VERSION 5.7 ;
  NOWIREEXTENSIONATPIN ON ;
  DIVIDERCHAR "/" ;
  BUSBITCHARS "[]" ;
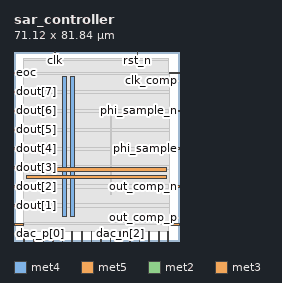
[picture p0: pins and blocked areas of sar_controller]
MACRO sar_controller
  CLASS BLOCK ;
  FOREIGN sar_controller ;
  ORIGIN 0.000 0.000 ;
  SIZE 71.120 BY 81.840 ;
  PIN VGND
    DIRECTION INOUT ;
    USE GROUND ;
    PORT
      LAYER met4 ;
        RECT 24.340 10.640 25.940 70.960 ;
    END
    PORT
      LAYER met5 ;
        RECT 5.280 30.030 65.560 31.630 ;
    END
  END VGND
  PIN VPWR
    DIRECTION INOUT ;
    USE POWER ;
    PORT
      LAYER met4 ;
        RECT 21.040 10.640 22.640 70.960 ;
    END
    PORT
      LAYER met5 ;
        RECT 5.280 26.730 65.560 28.330 ;
    END
  END VPWR
  PIN clk
    DIRECTION INPUT ;
    USE SIGNAL ;
    ANTENNAGATEAREA 1.704000 ;
    PORT
      LAYER met2 ;
        RECT 17.570 77.840 17.850 81.840 ;
    END
  END clk
  PIN clk_comp
    DIRECTION OUTPUT ;
    USE SIGNAL ;
    ANTENNADIFFAREA 0.340600 ;
    PORT
      LAYER met3 ;
        RECT 67.120 72.120 71.120 72.720 ;
    END
  END clk_comp
  PIN dac_n[0]
    DIRECTION OUTPUT ;
    USE SIGNAL ;
    ANTENNADIFFAREA 0.340600 ;
    PORT
      LAYER met2 ;
        RECT 37.350 0.000 37.630 4.000 ;
    END
  END dac_n[0]
  PIN dac_n[1]
    DIRECTION OUTPUT ;
    USE SIGNAL ;
    ANTENNADIFFAREA 0.340600 ;
    PORT
      LAYER met2 ;
        RECT 41.490 0.000 41.770 4.000 ;
    END
  END dac_n[1]
  PIN dac_n[2]
    DIRECTION OUTPUT ;
    USE SIGNAL ;
    ANTENNADIFFAREA 0.340600 ;
    PORT
      LAYER met2 ;
        RECT 45.630 0.000 45.910 4.000 ;
    END
  END dac_n[2]
  PIN dac_n[3]
    DIRECTION OUTPUT ;
    USE SIGNAL ;
    ANTENNADIFFAREA 0.340600 ;
    PORT
      LAYER met2 ;
        RECT 49.770 0.000 50.050 4.000 ;
    END
  END dac_n[3]
  PIN dac_n[4]
    DIRECTION OUTPUT ;
    USE SIGNAL ;
    ANTENNADIFFAREA 0.340600 ;
    PORT
      LAYER met2 ;
        RECT 53.910 0.000 54.190 4.000 ;
    END
  END dac_n[4]
  PIN dac_n[5]
    DIRECTION OUTPUT ;
    USE SIGNAL ;
    ANTENNADIFFAREA 0.340600 ;
    PORT
      LAYER met2 ;
        RECT 58.050 0.000 58.330 4.000 ;
    END
  END dac_n[5]
  PIN dac_n[6]
    DIRECTION OUTPUT ;
    USE SIGNAL ;
    ANTENNADIFFAREA 0.340600 ;
    PORT
      LAYER met2 ;
        RECT 62.190 0.000 62.470 4.000 ;
    END
  END dac_n[6]
  PIN dac_n[7]
    DIRECTION OUTPUT ;
    USE SIGNAL ;
    ANTENNADIFFAREA 0.340600 ;
    PORT
      LAYER met2 ;
        RECT 66.330 0.000 66.610 4.000 ;
    END
  END dac_n[7]
  PIN dac_p[0]
    DIRECTION OUTPUT ;
    USE SIGNAL ;
    ANTENNADIFFAREA 0.340600 ;
    PORT
      LAYER met2 ;
        RECT 4.230 0.000 4.510 4.000 ;
    END
  END dac_p[0]
  PIN dac_p[1]
    DIRECTION OUTPUT ;
    USE SIGNAL ;
    ANTENNADIFFAREA 0.340600 ;
    PORT
      LAYER met2 ;
        RECT 8.370 0.000 8.650 4.000 ;
    END
  END dac_p[1]
  PIN dac_p[2]
    DIRECTION OUTPUT ;
    USE SIGNAL ;
    ANTENNADIFFAREA 0.340600 ;
    PORT
      LAYER met2 ;
        RECT 12.510 0.000 12.790 4.000 ;
    END
  END dac_p[2]
  PIN dac_p[3]
    DIRECTION OUTPUT ;
    USE SIGNAL ;
    ANTENNADIFFAREA 0.340600 ;
    PORT
      LAYER met2 ;
        RECT 16.650 0.000 16.930 4.000 ;
    END
  END dac_p[3]
  PIN dac_p[4]
    DIRECTION OUTPUT ;
    USE SIGNAL ;
    ANTENNADIFFAREA 0.340600 ;
    PORT
      LAYER met2 ;
        RECT 20.790 0.000 21.070 4.000 ;
    END
  END dac_p[4]
  PIN dac_p[5]
    DIRECTION OUTPUT ;
    USE SIGNAL ;
    ANTENNADIFFAREA 0.340600 ;
    PORT
      LAYER met2 ;
        RECT 24.930 0.000 25.210 4.000 ;
    END
  END dac_p[5]
  PIN dac_p[6]
    DIRECTION OUTPUT ;
    USE SIGNAL ;
    ANTENNADIFFAREA 0.340600 ;
    PORT
      LAYER met2 ;
        RECT 29.070 0.000 29.350 4.000 ;
    END
  END dac_p[6]
  PIN dac_p[7]
    DIRECTION OUTPUT ;
    USE SIGNAL ;
    ANTENNADIFFAREA 0.340600 ;
    PORT
      LAYER met2 ;
        RECT 33.210 0.000 33.490 4.000 ;
    END
  END dac_p[7]
  PIN dout[0]
    DIRECTION OUTPUT ;
    USE SIGNAL ;
    ANTENNADIFFAREA 0.340600 ;
    PORT
      LAYER met3 ;
        RECT 0.000 6.840 4.000 7.440 ;
    END
  END dout[0]
  PIN dout[1]
    DIRECTION OUTPUT ;
    USE SIGNAL ;
    ANTENNADIFFAREA 0.340600 ;
    PORT
      LAYER met3 ;
        RECT 0.000 15.000 4.000 15.600 ;
    END
  END dout[1]
  PIN dout[2]
    DIRECTION OUTPUT ;
    USE SIGNAL ;
    ANTENNADIFFAREA 0.340600 ;
    PORT
      LAYER met3 ;
        RECT 0.000 23.160 4.000 23.760 ;
    END
  END dout[2]
  PIN dout[3]
    DIRECTION OUTPUT ;
    USE SIGNAL ;
    ANTENNADIFFAREA 0.340600 ;
    PORT
      LAYER met3 ;
        RECT 0.000 31.320 4.000 31.920 ;
    END
  END dout[3]
  PIN dout[4]
    DIRECTION OUTPUT ;
    USE SIGNAL ;
    ANTENNADIFFAREA 0.340600 ;
    PORT
      LAYER met3 ;
        RECT 0.000 39.480 4.000 40.080 ;
    END
  END dout[4]
  PIN dout[5]
    DIRECTION OUTPUT ;
    USE SIGNAL ;
    ANTENNADIFFAREA 0.340600 ;
    PORT
      LAYER met3 ;
        RECT 0.000 47.640 4.000 48.240 ;
    END
  END dout[5]
  PIN dout[6]
    DIRECTION OUTPUT ;
    USE SIGNAL ;
    ANTENNADIFFAREA 0.340600 ;
    PORT
      LAYER met3 ;
        RECT 0.000 55.800 4.000 56.400 ;
    END
  END dout[6]
  PIN dout[7]
    DIRECTION OUTPUT ;
    USE SIGNAL ;
    ANTENNADIFFAREA 0.340600 ;
    PORT
      LAYER met3 ;
        RECT 0.000 63.960 4.000 64.560 ;
    END
  END dout[7]
  PIN eoc
    DIRECTION OUTPUT ;
    USE SIGNAL ;
    ANTENNADIFFAREA 0.340600 ;
    PORT
      LAYER met3 ;
        RECT 0.000 72.120 4.000 72.720 ;
    END
  END eoc
  PIN out_comp_n
    DIRECTION INPUT ;
    USE SIGNAL ;
    PORT
      LAYER met3 ;
        RECT 67.120 23.160 71.120 23.760 ;
    END
  END out_comp_n
  PIN out_comp_p
    DIRECTION INPUT ;
    USE SIGNAL ;
    ANTENNAGATEAREA 0.196500 ;
    PORT
      LAYER met3 ;
        RECT 67.120 6.840 71.120 7.440 ;
    END
  END out_comp_p
  PIN phi_sample
    DIRECTION OUTPUT ;
    USE SIGNAL ;
    ANTENNADIFFAREA 0.340600 ;
    PORT
      LAYER met3 ;
        RECT 67.120 39.480 71.120 40.080 ;
    END
  END phi_sample
  PIN phi_sample_n
    DIRECTION OUTPUT ;
    USE SIGNAL ;
    ANTENNADIFFAREA 0.340600 ;
    PORT
      LAYER met3 ;
        RECT 67.120 55.800 71.120 56.400 ;
    END
  END phi_sample_n
  PIN rst_n
    DIRECTION INPUT ;
    USE SIGNAL ;
    ANTENNAGATEAREA 0.196500 ;
    PORT
      LAYER met2 ;
        RECT 52.990 77.840 53.270 81.840 ;
    END
  END rst_n
  OBS
      LAYER nwell ;
        RECT 5.330 10.795 65.510 70.805 ;
      LAYER li1 ;
        RECT 5.520 10.795 65.320 70.805 ;
      LAYER met1 ;
        RECT 4.210 10.640 66.630 70.960 ;
      LAYER met2 ;
        RECT 4.230 77.560 17.290 78.610 ;
        RECT 18.130 77.560 52.710 78.610 ;
        RECT 53.550 77.560 66.600 78.610 ;
        RECT 4.230 4.280 66.600 77.560 ;
        RECT 4.790 4.000 8.090 4.280 ;
        RECT 8.930 4.000 12.230 4.280 ;
        RECT 13.070 4.000 16.370 4.280 ;
        RECT 17.210 4.000 20.510 4.280 ;
        RECT 21.350 4.000 24.650 4.280 ;
        RECT 25.490 4.000 28.790 4.280 ;
        RECT 29.630 4.000 32.930 4.280 ;
        RECT 33.770 4.000 37.070 4.280 ;
        RECT 37.910 4.000 41.210 4.280 ;
        RECT 42.050 4.000 45.350 4.280 ;
        RECT 46.190 4.000 49.490 4.280 ;
        RECT 50.330 4.000 53.630 4.280 ;
        RECT 54.470 4.000 57.770 4.280 ;
        RECT 58.610 4.000 61.910 4.280 ;
        RECT 62.750 4.000 66.050 4.280 ;
      LAYER met3 ;
        RECT 4.400 71.720 66.720 72.585 ;
        RECT 3.990 64.960 67.120 71.720 ;
        RECT 4.400 63.560 67.120 64.960 ;
        RECT 3.990 56.800 67.120 63.560 ;
        RECT 4.400 55.400 66.720 56.800 ;
        RECT 3.990 48.640 67.120 55.400 ;
        RECT 4.400 47.240 67.120 48.640 ;
        RECT 3.990 40.480 67.120 47.240 ;
        RECT 4.400 39.080 66.720 40.480 ;
        RECT 3.990 32.320 67.120 39.080 ;
        RECT 4.400 30.920 67.120 32.320 ;
        RECT 3.990 24.160 67.120 30.920 ;
        RECT 4.400 22.760 66.720 24.160 ;
        RECT 3.990 16.000 67.120 22.760 ;
        RECT 4.400 14.600 67.120 16.000 ;
        RECT 3.990 7.840 67.120 14.600 ;
        RECT 4.400 6.975 66.720 7.840 ;
      LAYER met4 ;
        RECT 41.695 19.895 42.025 56.265 ;
  END
END sar_controller
END LIBRARY

